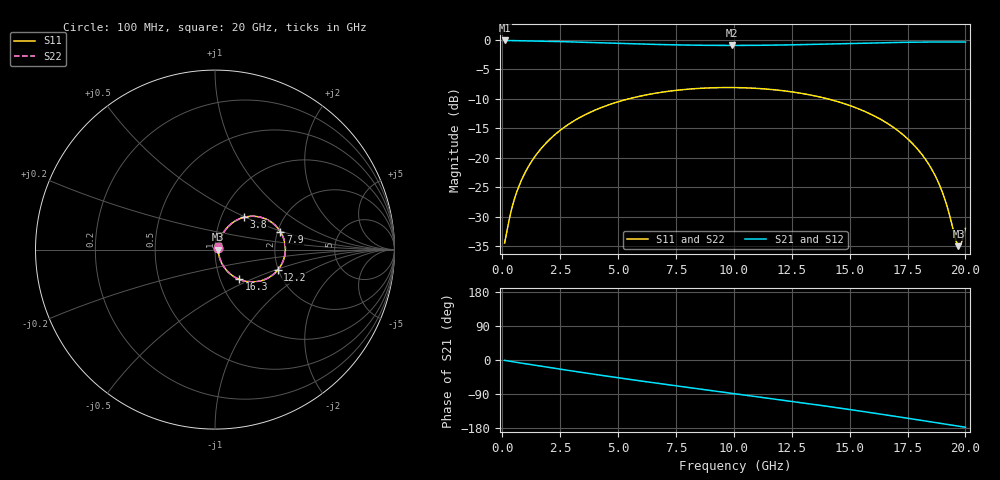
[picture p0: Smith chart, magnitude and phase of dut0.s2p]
! Touchstone file exported from HFSS 2026.1.0
!  File:  C:/ffzhzh/LocalFiles/Ansys_Project_Files/temp_test_TSV_RDL_0_1782978415_6388.aedt
!  Generated:  03:56:30 PM Jul  2, 2026
!  Design:  TSV_RDL
!  Project:  temp_test_TSV_RDL_0_1782978415_6388
! Variables:
!  h_bsmrdl = 3.82um
!  h_ox = 20um
!  h_rdl = 5um
!  h_sub = 83.82um
!  h_tmrdl = 2.44um
!  h_tsv = 83.82um
!  h_via = 3um
!  l_bsmrdl = 247.62um
!  l_sub = 2842.42um
!  l_tmrdl = 396.75um
!  m_sub = 200um
!  pitch = 35.74um
!  r_tsv = 7.44um
!  s_tmrdl = 10um
!  w_bsmrdl = 16.14um
!  w_sub = 500um
!  w_tmrdl = 21.38um
!  x_tsv_center1 = 407.44um
!  x_tsv_center2 = 671.2um
!  x_tsv_center3 = 1089.33um
!  x_tsv_center4 = 1353.09um
!  x_tsv_center5 = 1771.22um
!  x_tsv_center6 = 2034.98um
# GHz S MA R 50.000000
! Terminal data exported
! Port[1] = TM_RDL1_1_T1
! Port[2] = TM_RDL5_1_T1
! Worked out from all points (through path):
!   200 points, 100 MHz to 20 GHz, reference 50 ohm
!   highest |S21| = -0.15 dB at 100 MHz (marker M1); lowest = -1.0 dB at 9.9 GHz (marker M2)
!   group delay of S21, straight-line fit = 24 ps
!   lowest |S11| = -35.0 dB at 19.7 GHz (marker M3), VSWR 1.04, Z = 51.8 - j0.104 ohm
!   |S11| at or under -10 dB: start of sweep to 5.507 GHz; 14 GHz to end of sweep
!   |S22| runs from -35.0 to -8.1 dB; largest |S21 - S12| = 6.3e-13
!   S11 on the Smith chart (normalised r, x): 100 MHz: 1.03, +0.02; 3.8 GHz: 1.28, +0.49; 7.9 GHz: 2.07, +0.48; 12.2 GHz: 1.98, -0.53; 16.3 GHz: 1.23, -0.43; 20 GHz: 1.04, +0.04
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0.1  0.01883 24.5  0.983 -1.0  0.983 -1.0  0.01883 24.5
! Gamma 0 0 0 0
! Port Impedance 50 0 50 0
0.4  0.03636 54.6  0.9807 -4.1  0.9807 -4.1  0.03636 54.6
0.6  0.04947 60.0  0.9788 -6.1  0.9788 -6.1  0.04947 60.0
1.2  0.08853 63.7  0.9738 -11.8  0.9738 -11.8  0.08853 63.7
2.2  0.152 59.8  0.9646 -21.3  0.9646 -21.3  0.152 59.8
3.5  0.2266 50.4  0.9491 -33.4  0.9491 -33.4  0.2266 50.4
3.8  0.2421 48.0  0.9452 -36.2  0.9452 -36.2  0.2421 48.0
6.8  0.3557 24.0  0.908 -62.3  0.908 -62.3  0.3557 24.0
7.9  0.3779 15.3  0.8988 -71.4  0.8988 -71.4  0.3779 15.3
9.9  0.392 -0.3  0.8921 -87.7  0.8921 -87.7  0.3921 -0.3
10.1  0.3916 -1.9  0.8921 -89.3  0.8921 -89.3  0.3916 -1.9
12.2  0.367 -18.3  0.9003 -106.6  0.9003 -106.6  0.367 -18.3
13.4  0.3362 -27.9  0.9102 -116.7  0.9102 -116.7  0.3362 -27.9
16.3  0.213 -51.1  0.9395 -142.5  0.9395 -142.5  0.213 -51.1
16.7  0.1911 -54.1  0.943 -146.2  0.943 -146.2  0.1911 -54.1
17.7  0.1323 -60.9  0.9502 -155.5  0.9502 -155.5  0.1324 -60.8
18.5  0.08251 -63.6  0.9535 -163.1  0.9535 -163.1  0.08256 -63.5
19.1  0.04507 -58.5  0.9545 -168.8  0.9545 -168.8  0.04515 -58.4
19.6  0.01957 -21.9  0.9541 -173.6  0.9541 -173.6  0.01968 -21.9
19.7  0.01773 -3.2  0.954 -174.6  0.954 -174.6  0.01784 -3.3
19.8  0.01824 16.9  0.9537 -175.5  0.9537 -175.5  0.01834 16.7
20  0.02511 45.6  0.9531 -177.4  0.9531 -177.4  0.02516 45.3
